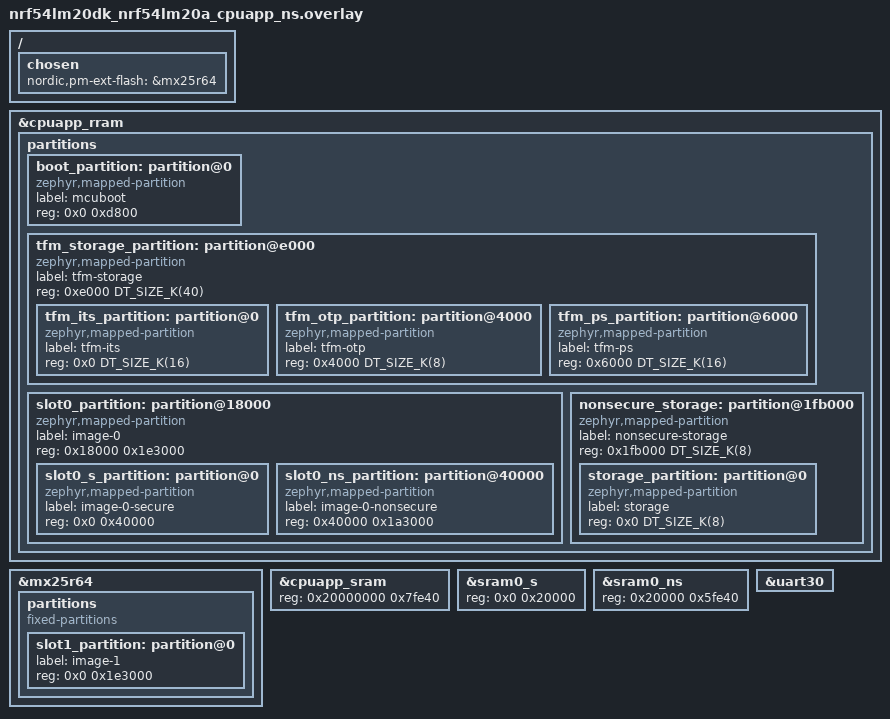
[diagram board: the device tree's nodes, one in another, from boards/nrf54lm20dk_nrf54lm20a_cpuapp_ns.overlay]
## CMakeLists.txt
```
#
# Copyright (c) 2020 Nordic Semiconductor
#
# SPDX-License-Identifier: LicenseRef-Nordic-5-Clause
#

cmake_minimum_required(VERSION 3.20.0)

find_package(Zephyr REQUIRED HINTS $ENV{ZEPHYR_BASE})

project(azure_iot_hub)

# NORDIC SDK APP START
target_sources(app PRIVATE src/main.c)
# NORDIC SDK APP END

zephyr_include_directories(src)
```

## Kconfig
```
#
# Copyright (c) 2022 Nordic Semiconductor ASA
#
# SPDX-License-Identifier: LicenseRef-Nordic-5-Clause
#

menu "Azure IoT Hub sample"

module = AZURE_IOT_HUB_SAMPLE
module-str = Azure IoT Hub sample
source "$(ZEPHYR_BASE)/subsys/logging/Kconfig.template.log_config"

config AZURE_IOT_HUB_SAMPLE_DEVICE_ID_USE_HW_ID
	bool "Use HW ID as device ID"
	select HW_ID_LIBRARY
	help
	  Use the devices's hardware ID as device ID when connecting to Azure IOT Hub

config AZURE_IOT_HUB_SAMPLE_CONNECTION_RETRY_TIMEOUT_SECONDS
	int "Number of seconds between each Azure IoT Hub connection retry"
	default 30
	help
	  If the connection fails, the sample tries to connect again at this interval.

endmenu

menu "Zephyr Kernel"
source "Kconfig.zephyr"
endmenu
```

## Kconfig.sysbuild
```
#
# Copyright (c) 2024 Nordic Semiconductor
#
# SPDX-License-Identifier: LicenseRef-Nordic-5-Clause
#

choice BOOTLOADER
	default BOOTLOADER_MCUBOOT if !BOARD_NATIVE_SIM
endchoice

config WIFI_NRF70
	default y if BOARD_NRF7002DK_NRF5340_CPUAPP_NS || \
		BOARD_NRF54LM20DK_NRF54LM20A_CPUAPP_NS || \
		BOARD_NRF54LM20DK_NRF54LM20B_CPUAPP_NS

source "share/sysbuild/Kconfig"
```

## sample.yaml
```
sample:
  name: Azure IoT Hub sample
tests:
  sample.net.azure_iot_hub:
    sysbuild: true
    build_only: true
    integration_platforms:
      - nrf9151dk/nrf9151/ns
      - native_sim
    platform_allow:
      - nrf9151dk/nrf9151/ns
      - native_sim
    tags:
      - ci_build
      - sysbuild
      - ci_samples_net
  sample.net.azure_iot_hub.wifi:
    sysbuild: true
    build_only: true
    integration_platforms:
      - nrf7002dk/nrf5340/cpuapp/ns
    platform_allow:
      - nrf7002dk/nrf5340/cpuapp/ns
    extra_args:
      - azure_iot_hub_EXTRA_CONF_FILE="wifi.conf"
    tags:
      - ci_build
      - sysbuild
      - ci_samples_net
  sample.net.azure_iot_hub.nrf7120.wifi:
    sysbuild: true
    build_only: true
    integration_platforms:
      - nrf7120dk/nrf7120/cpuapp/ns
    platform_allow:
      - nrf7120dk/nrf7120/cpuapp/ns
    extra_args:
      - azure_iot_hub_EXTRA_CONF_FILE="wifi.conf"
    tags:
      - ci_build
      - sysbuild
      - ci_samples_net
  sample.net.azure_iot_hub.nrf54lm20_nrf7002eb2.wifi:
    sysbuild: true
    build_only: true
    build_on_all: true
    integration_platforms:
      - nrf54lm20dk/nrf54lm20a/cpuapp/ns
      - nrf54lm20dk/nrf54lm20b/cpuapp/ns
    platform_allow:
      - nrf54lm20dk/nrf54lm20a/cpuapp/ns
      - nrf54lm20dk/nrf54lm20b/cpuapp/ns
    extra_args:
      - azure_iot_hub_SHIELD="nrf7002eb2"
      - azure_iot_hub_EXTRA_CONF_FILE="wifi.conf"
    tags:
      - ci_build
      - sysbuild
      - ci_samples_net
  sample.net.azure_iot_hub.dps:
    sysbuild: true
    build_only: true
    integration_platforms:
      - nrf9151dk/nrf9151/ns
    platform_allow:
      - nrf9151dk/nrf9151/ns
    extra_args:
      - azure_iot_hub_EXTRA_CONF_FILE=dps.conf
    extra_configs:
      - CONFIG_AZURE_IOT_HUB_DPS_ID_SCOPE="test-scope"
    tags:
      - ci_build
      - sysbuild
      - ci_samples_net
  sample.net.azure_iot_hub.dps.wifi:
    sysbuild: true
    build_only: true
    integration_platforms:
      - nrf7002dk/nrf5340/cpuapp/ns
    platform_allow:
      - nrf7002dk/nrf5340/cpuapp/ns
    extra_args:
      - azure_iot_hub_EXTRA_CONF_FILE="wifi.conf;dps.conf"
    extra_configs:
      - CONFIG_AZURE_IOT_HUB_DPS_ID_SCOPE="test-scope"
    tags:
      - ci_build
      - sysbuild
      - ci_samples_net
  sample.net.azure_iot_hub.dps.nrf7120.wifi:
    sysbuild: true
    build_only: true
    integration_platforms:
      - nrf7120dk/nrf7120/cpuapp/ns
    platform_allow:
      - nrf7120dk/nrf7120/cpuapp/ns
    extra_args:
      - azure_iot_hub_EXTRA_CONF_FILE="wifi.conf;dps.conf"
    extra_configs:
      - CONFIG_AZURE_IOT_HUB_DPS_ID_SCOPE="test-scope"
    tags:
      - ci_build
      - sysbuild
      - ci_samples_net
  sample.net.azure_iot_hub.dps.nrf54lm20_nrf7002eb2.wifi:
    sysbuild: true
    build_only: true
    build_on_all: true
    integration_platforms:
      - nrf54lm20dk/nrf54lm20a/cpuapp/ns
      - nrf54lm20dk/nrf54lm20b/cpuapp/ns
    platform_allow:
      - nrf54lm20dk/nrf54lm20a/cpuapp/ns
      - nrf54lm20dk/nrf54lm20b/cpuapp/ns
    extra_args:
      - azure_iot_hub_SHIELD="nrf7002eb2"
      - azure_iot_hub_EXTRA_CONF_FILE="wifi.conf;dps.conf"
    extra_configs:
      - CONFIG_AZURE_IOT_HUB_DPS_ID_SCOPE="test-scope"
    tags:
      - ci_build
      - sysbuild
      - ci_samples_net
```

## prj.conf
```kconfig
#
# Copyright (c) 2020 Nordic Semiconductor ASA
#
# SPDX-License-Identifier: LicenseRef-Nordic-5-Clause
#

# General config
CONFIG_REBOOT=y
CONFIG_ASSERT=y

# Logging
CONFIG_LOG=y
CONFIG_LOG_MODE_DEFERRED=y

# Network
CONFIG_NETWORKING=y
CONFIG_NET_NATIVE=y
CONFIG_NET_IPV4=y
CONFIG_NET_CONNECTION_MANAGER=y

# Azure IoT Hub library
CONFIG_AZURE_IOT_HUB=y
CONFIG_AZURE_IOT_HUB_DEVICE_ID="my-device"
# Host name must be configured if DPS is not used
CONFIG_AZURE_IOT_HUB_HOSTNAME=""
# Change the security tag to the tag where Azure IoT Hub certificates
# are provisioned
CONFIG_MQTT_HELPER_SEC_TAG=10
CONFIG_MQTT_HELPER_STACK_SIZE=8192

# Uncomment to get more verbose logging when debugging
# CONFIG_AZURE_IOT_HUB_LOG_LEVEL_DBG=y

# MQTT - Maximum MQTT keepalive timeout specified by Azure IoT Hub
CONFIG_MQTT_KEEPALIVE=1767

# cJSON
CONFIG_CJSON_LIB=y

# Settings, needed for Azure Device Provisioning Service
CONFIG_FLASH=y
CONFIG_FLASH_MAP=y
CONFIG_FCB=y
CONFIG_SETTINGS=y
CONFIG_SETTINGS_FCB=n
CONFIG_MPU_ALLOW_FLASH_WRITE=y
```

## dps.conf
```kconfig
#
# Copyright (c) 2022 Nordic Semiconductor ASA
#
# SPDX-License-Identifier: LicenseRef-Nordic-5-Clause
#

CONFIG_AZURE_IOT_HUB_DPS=y

# The ID scope can be omitted and provided at run time
CONFIG_AZURE_IOT_HUB_DPS_ID_SCOPE=""

CONFIG_NVS=y
CONFIG_SETTINGS_NVS=y
```

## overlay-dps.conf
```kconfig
#
# Copyright (c) 2022 Nordic Semiconductor ASA
#
# SPDX-License-Identifier: LicenseRef-Nordic-5-Clause
#

CONFIG_AZURE_IOT_HUB_DPS=y

# The ID scope can be omitted and provided at run time
CONFIG_AZURE_IOT_HUB_DPS_ID_SCOPE=""
```

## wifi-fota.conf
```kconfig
#
# Copyright (c) 2026 Nordic Semiconductor ASA
#
# SPDX-License-Identifier: LicenseRef-Nordic-5-Clause
#

# Azure FOTA over MCUboot.

# Azure FOTA
CONFIG_AZURE_FOTA=y
CONFIG_AZURE_FOTA_APP_VERSION_AUTO=n
CONFIG_AZURE_FOTA_TLS=y
# Change the security tag to the tag where the certificates are provisioned
# for the server where the FOTA image is hosted
CONFIG_AZURE_FOTA_SEC_TAG=11
CONFIG_FOTA_DOWNLOAD=y
CONFIG_DFU_TARGET=y

# FOTA storage backend: MCUboot image manager + streaming downloader
CONFIG_FLASH=y
CONFIG_FLASH_MAP=y
CONFIG_MCUBOOT_IMG_MANAGER=y
CONFIG_IMG_MANAGER=y
CONFIG_STREAM_FLASH=y
CONFIG_IMG_ERASE_PROGRESSIVELY=y
CONFIG_DOWNLOADER=y
CONFIG_DOWNLOADER_STACK_SIZE=4096
```

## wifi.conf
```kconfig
#
# Copyright (c) 2026 Nordic Semiconductor ASA
#
# SPDX-License-Identifier: LicenseRef-Nordic-5-Clause
#

# Common Wi-Fi + networking + TLS configuration shared by all Wi-Fi builds of
# this sample (nRF70 and nRF71).

# Logging
CONFIG_NET_LOG=y

# Wi-Fi
CONFIG_WIFI=y
CONFIG_WIFI_NM_WPA_SUPPLICANT=y
CONFIG_WIFI_NM_WPA_SUPPLICANT_LOG_LEVEL_ERR=y
CONFIG_WIFI_NRF70_LOG_LEVEL_ERR=y
CONFIG_NET_L2_ETHERNET=y

# nRF70/nRF71 driver tuning. The two drivers use different symbol prefixes (NRF70_* for the
# external nRF7002, NRF71_* for the integrated nRF7120 Wi-Fi), so both sets are listed with
# matching values. Each set is a no-op on the board that uses the other driver.
CONFIG_WIFI_CREDENTIALS=y

# Zephyr NET Connection Manager Connectivity layer.
CONFIG_L2_WIFI_CONNECTIVITY=y
CONFIG_L2_WIFI_CONNECTIVITY_AUTO_CONNECT=n
CONFIG_L2_WIFI_CONNECTIVITY_AUTO_DOWN=n

# DNS
CONFIG_DNS_RESOLVER=y
CONFIG_NET_SOCKETS_DNS_TIMEOUT=30000

# NET sockets
CONFIG_NET_SOCKETS=y
CONFIG_NET_TCP=y
CONFIG_NET_UDP=y
CONFIG_NET_SOCKETS_OFFLOAD=n
CONFIG_NET_DHCPV4=y
# Run DHCPv6 on RA, covering both stateful and stateless configurations
CONFIG_NET_DHCPV6=y
CONFIG_NET_DHCPV6_START_ON_RA=y
CONFIG_NET_CONTEXT_SNDTIMEO=y
CONFIG_NET_CONTEXT_RCVTIMEO=y

# Shell
CONFIG_SHELL=y
CONFIG_SHELL_STACK_SIZE=8192
CONFIG_NET_L2_WIFI_SHELL=y

# General
CONFIG_POSIX_TIMERS=y
CONFIG_HW_ID_LIBRARY=y
CONFIG_HW_ID_LIBRARY_SOURCE_NET_MAC=y
CONFIG_DK_LIBRARY=y

# Heap and stacks
CONFIG_MAIN_STACK_SIZE=6144
CONFIG_SYSTEM_WORKQUEUE_STACK_SIZE=4096
CONFIG_HEAP_MEM_POOL_SIZE=40144
CONFIG_HEAP_MEM_POOL_IGNORE_MIN=y
CONFIG_NET_RX_STACK_SIZE=4096
CONFIG_NET_SOCKETS_SERVICE_STACK_SIZE=2048
CONFIG_NRF_WIFI_DATA_HEAP_SIZE=65536

# TLS networking
CONFIG_NET_SOCKETS_SOCKOPT_TLS=y
CONFIG_NET_SOCKETS_ENABLE_DTLS=n
CONFIG_NET_SOCKETS_TLS_MAX_CONTEXTS=2
# Persist TLS credentials across reboots.
CONFIG_TLS_CREDENTIALS_BACKEND_PROTECTED_STORAGE=y

# mbedTLS
CONFIG_MBEDTLS=y
CONFIG_MBEDTLS_ENABLE_HEAP=y
# Fits the MQTT and FOTA download TLS connections at the same time.
CONFIG_MBEDTLS_HEAP_SIZE=98304
CONFIG_MBEDTLS_SSL_KEEP_PEER_CERTIFICATE=n
CONFIG_MBEDTLS_SSL_SERVER_NAME_INDICATION=y
# Set MPI (Multiple Precision Integer) size limit to 512 bytes for handling of 4 kb certificates
# in cryptographic operations.
CONFIG_MBEDTLS_MPI_MAX_SIZE=512
# PSA crypto not covered by the ciphersuite: ECDSA for server cert chain verification
CONFIG_PSA_WANT_ALG_ECDSA=y
# Azure Blob Storage, the FOTA host, uses an RSA 4096-bit CA certificate chain.
# Keep RSA 2048 enabled for the Azure IoT Hub chain, as it is no longer the
# default when another key size is enabled.
CONFIG_PSA_WANT_RSA_KEY_SIZE_2048=y
CONFIG_PSA_WANT_RSA_KEY_SIZE_4096=y
# TLS crypto via one ciphersuite config
CONFIG_MBEDTLS_CIPHERSUITE_TLS_ECDHE_RSA_WITH_AES_128_GCM_SHA256=y

# Enable LTO to save flash memory
CONFIG_LTO=y
CONFIG_ISR_TABLES_LOCAL_DECLARATION=y

# Floating-point printf support
CONFIG_CBPRINTF_FP_SUPPORT=y
CONFIG_LOG_PROCESS_THREAD_STACK_SIZE=4096

# Azure FOTA
CONFIG_AZURE_FOTA=y
CONFIG_AZURE_FOTA_APP_VERSION_AUTO=n
CONFIG_AZURE_FOTA_TLS=y
# Set the same security tag as for CONFIG_MQTT_HELPER_SEC_TAG since the same CA
# certificate is used to validate the server hosting the firmware image.
CONFIG_AZURE_FOTA_SEC_TAG=10
CONFIG_FOTA_DOWNLOAD=y
CONFIG_DFU_TARGET=y

# FOTA storage backend: MCUboot image manager + streaming downloader
CONFIG_FLASH=y
CONFIG_FLASH_MAP=y
CONFIG_MCUBOOT_IMG_MANAGER=y
CONFIG_IMG_MANAGER=y
CONFIG_STREAM_FLASH=y
CONFIG_IMG_ERASE_PROGRESSIVELY=y
CONFIG_DOWNLOADER=y
CONFIG_DOWNLOADER_STACK_SIZE=4096
```

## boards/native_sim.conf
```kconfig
#
# Copyright (c) 2023 Nordic Semiconductor ASA
#
# SPDX-License-Identifier: LicenseRef-Nordic-5-Clause
#

# Heap and stacks
CONFIG_HEAP_MEM_POOL_SIZE=1280

# Networking config
CONFIG_NET_TCP=y
CONFIG_NET_UDP=y
CONFIG_NET_SOCKETS=y
CONFIG_POSIX_API=y
CONFIG_NET_SOCKETS_SOCKOPT_TLS=y
CONFIG_NET_PKT_RX_COUNT=32
CONFIG_NET_PKT_TX_COUNT=32
CONFIG_NET_BUF_RX_COUNT=32
CONFIG_NET_BUF_TX_COUNT=32
CONFIG_NET_IF_UNICAST_IPV6_ADDR_COUNT=3
CONFIG_NET_IF_MCAST_IPV6_ADDR_COUNT=4
CONFIG_NET_MAX_CONTEXTS=10
CONFIG_NET_L2_ETHERNET=y
CONFIG_NET_CONTEXT_SNDTIMEO=y

CONFIG_ETH_NATIVE_TAP=y

# Network driver config
CONFIG_TEST_RANDOM_GENERATOR=y

# TLS configuration
CONFIG_MBEDTLS=y
CONFIG_MBEDTLS_ENABLE_HEAP=y
CONFIG_MBEDTLS_HEAP_SIZE=40000
CONFIG_MBEDTLS_SSL_MAX_CONTENT_LEN=7168
CONFIG_MBEDTLS_PEM_PARSE_C=y
CONFIG_MBEDTLS_PEM_WRITE_C=y
CONFIG_MBEDTLS_CIPHERSUITE_TLS_ECDHE_RSA_WITH_AES_128_CBC_SHA256=y

# DNS
CONFIG_DNS_RESOLVER=y
CONFIG_DNS_SERVER_IP_ADDRESSES=y
CONFIG_DNS_SERVER1="8.8.8.8"
CONFIG_DNS_RESOLVER_MAX_SERVERS=2

# Network address config
CONFIG_NET_CONFIG_SETTINGS=y
CONFIG_NET_CONFIG_NEED_IPV4=y
CONFIG_NET_CONFIG_MY_IPV4_ADDR="192.0.2.1"
CONFIG_NET_CONFIG_MY_IPV4_GW="192.0.2.2"

# Azure IoT Hub library
CONFIG_MQTT_HELPER_SEC_TAG=201
```

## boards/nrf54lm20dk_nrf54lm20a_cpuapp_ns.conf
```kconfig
#
# Copyright (c) 2026 Nordic Semiconductor ASA
#
# SPDX-License-Identifier: LicenseRef-Nordic-5-Clause
#

# External flash driver for the MCUboot secondary slot
CONFIG_SPI=y
CONFIG_SPI_NOR=y
CONFIG_SPI_NOR_SFDP_DEVICETREE=y

# Necessary for TLS with MM-less IOVEC.
# 36864 = 2 * MBEDTLS_SSL_MAX_CONTENT_LEN (16384) + overhead
CONFIG_TFM_CRYPTO_IOVEC_BUFFER_SIZE=36864

# Configure TF-M
CONFIG_TFM_PROFILE_TYPE_NOT_SET=y
# TF-M and nRF7002EB2 shield use the same UART30. TF-M assigns UART30 to secure environment, which
# causes BusFault when app tries to access it. Disabling logging in TF-M prevent it using UART30.
CONFIG_TFM_LOG_LEVEL_SILENCE=y
```

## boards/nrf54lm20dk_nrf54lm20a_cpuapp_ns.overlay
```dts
/*
 * Copyright (c) 2026 Nordic Semiconductor ASA
 *
 * SPDX-License-Identifier: LicenseRef-Nordic-5-Clause
 */

/ {
	/* Configure partition manager to use mx25r64 as the external flash */
	chosen {
		nordic,pm-ext-flash = &mx25r64;
	};
};

/delete-node/ &slot0_partition;
/delete-node/ &tfm_ps_partition;
/delete-node/ &tfm_its_partition;
/delete-node/ &tfm_otp_partition;
/delete-node/ &slot0_ns_partition;
/delete-node/ &storage_partition;

&cpuapp_rram {
	partitions {
		boot_partition: partition@0 {
			compatible = "zephyr,mapped-partition";
			label = "mcuboot";
			reg = <0x0 0xd800>;
		};

		tfm_storage_partition: partition@e000 {
			compatible = "zephyr,mapped-partition";
			label = "tfm-storage";
			reg = <0xe000 DT_SIZE_K(40)>;
			ranges = <0x0 0xe000 DT_SIZE_K(40)>;
			#address-cells = <1>;
			#size-cells = <1>;

			tfm_its_partition: partition@0 {
				compatible = "zephyr,mapped-partition";
				label = "tfm-its";
				reg = <0x0 DT_SIZE_K(16)>;
			};

			tfm_otp_partition: partition@4000 {
				compatible = "zephyr,mapped-partition";
				label = "tfm-otp";
				reg = <0x4000 DT_SIZE_K(8)>;
			};

			tfm_ps_partition: partition@6000 {
				compatible = "zephyr,mapped-partition";
				label = "tfm-ps";
				reg = <0x6000 DT_SIZE_K(16)>;
			};
		};

		slot0_partition: partition@18000 {
			compatible = "zephyr,mapped-partition";
			label = "image-0";
			reg = <0x18000 0x1e3000>;
			ranges = <0x0 0x18000 0x1e3000>;
			#address-cells = <1>;
			#size-cells = <1>;

			slot0_s_partition: partition@0 {
				compatible = "zephyr,mapped-partition";
				label = "image-0-secure";
				reg = <0x0 0x40000>;
			};

			slot0_ns_partition: partition@40000 {
				compatible = "zephyr,mapped-partition";
				label = "image-0-nonsecure";
				reg = <0x40000 0x1a3000>;
			};
		};

		nonsecure_storage: partition@1fb000 {
			compatible = "zephyr,mapped-partition";
			label = "nonsecure-storage";
			reg = <0x1fb000 DT_SIZE_K(8)>;
			ranges = <0x0 0x1fb000 DT_SIZE_K(8)>;
			#address-cells = <1>;
			#size-cells = <1>;

			storage_partition: partition@0 {
				compatible = "zephyr,mapped-partition";
				label = "storage";
				reg = <0x0 DT_SIZE_K(8)>;
			};
		};
	};
};

&mx25r64 {
	status = "okay";

	partitions {
		compatible = "fixed-partitions";
		#address-cells = <1>;
		#size-cells = <1>;

		slot1_partition: partition@0 {
			label = "image-1";
			reg = <0x0 0x1e3000>;
		};
	};
};

/*
 * CPUAPP SRAM TrustZone split: TF-M uses the first 128 KiB (&sram0_s, reg 0x20000); the NS
 * workload uses the remainder (&sram0_ns). These sizes must match the TF-M platform RAM
 * layout for nRF54LM20.
 */
&cpuapp_sram {
	reg = <0x20000000 0x7fe40>;
	ranges = <0x0 0x20000000 0x7fe40>;
};

&sram0_s {
	reg = <0x0 0x20000>;
	ranges = <0x0 0x0 0x20000>;
};

&sram0_ns {
	reg = <0x20000 0x5fe40>;
	ranges = <0x0 0x20000 0x5fe40>;
};

/*
 * Board NS DTS keeps &uart30 disabled for the default TF-M UARTE30 logging case.
 * With CONFIG_TFM_LOG_LEVEL_SILENCE=y TF-M does not use that UART; re-enable UARTE30 for NS.
 */
&uart30 {
	status = "okay";
};

/*
 * This layout redefines the flash partition map, dropping partitions that the
 * upstream nordic-tz-secure/-nonsecure descriptors reference. Remove the
 * descriptors so they do not hold dangling phandles (restores the behaviour
 * from before the descriptors were introduced).
 */
/ {
	/delete-node/ nordic-tz-secure;
	/delete-node/ nordic-tz-nonsecure;
};
```

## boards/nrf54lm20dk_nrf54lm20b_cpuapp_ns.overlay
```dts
/*
 * Copyright (c) 2026 Nordic Semiconductor ASA
 *
 * SPDX-License-Identifier: LicenseRef-Nordic-5-Clause
 */

/delete-node/ &slot0_s_partition;
/delete-node/ &tfm_ps_partition;
/delete-node/ &tfm_its_partition;
/delete-node/ &tfm_otp_partition;
/delete-node/ &slot0_ns_partition;
/delete-node/ &storage_partition;

&cpuapp_rram {
	partitions {
		boot_partition: partition@0 {
			compatible = "zephyr,mapped-partition";
			label = "mcuboot";
			reg = <0x0 0x10000>;
		};

		tfm_storage_partition: partition@10000 {
			compatible = "zephyr,mapped-partition";
			label = "tfm-storage";
			reg = <0x10000 DT_SIZE_K(40)>;
			ranges = <0x0 0x10000 DT_SIZE_K(40)>;
			#address-cells = <1>;
			#size-cells = <1>;

			tfm_its_partition: partition@0 {
				compatible = "zephyr,mapped-partition";
				label = "tfm-its";
				reg = <0x0 DT_SIZE_K(16)>;
			};

			tfm_otp_partition: partition@4000 {
				compatible = "zephyr,mapped-partition";
				label = "tfm-otp";
				reg = <0x4000 DT_SIZE_K(8)>;
			};

			tfm_ps_partition: partition@6000 {
				compatible = "zephyr,mapped-partition";
				label = "tfm-ps";
				reg = <0x6000 DT_SIZE_K(16)>;
			};
		};

		slot0_partition: partition@1a000 {
			compatible = "zephyr,mapped-partition";
			label = "image-0";
			reg = <0x1a000 0x1e1000>;
			ranges = <0x0 0x1a000 0x1e1000>;
			#address-cells = <1>;
			#size-cells = <1>;

			slot0_s_partition: partition@0 {
				compatible = "zephyr,mapped-partition";
				label = "image-0-secure";
				reg = <0x0 0x40000>;
			};

			slot0_ns_partition: partition@40000 {
				compatible = "zephyr,mapped-partition";
				label = "image-0-nonsecure";
				reg = <0x40000 0x1a1000>;
			};
		};

		nonsecure_storage: partition@1fb000 {
			compatible = "zephyr,mapped-partition";
			label = "nonsecure-storage";
			reg = <0x1fb000 DT_SIZE_K(8)>;
			ranges = <0x0 0x1fb000 DT_SIZE_K(8)>;
			#address-cells = <1>;
			#size-cells = <1>;

			storage_partition: partition@0 {
				compatible = "zephyr,mapped-partition";
				label = "storage";
				reg = <0x0 DT_SIZE_K(8)>;
			};
		};
	};
};

&mx25r64 {
	status = "okay";

	partitions {
		compatible = "fixed-partitions";
		#address-cells = <1>;
		#size-cells = <1>;

		slot1_partition: partition@0 {
			label = "image-1";
			reg = <0x0 0x1e1000>;
		};
	};
};

/*
 * CPUAPP SRAM TrustZone split: TF-M uses the first 128 KiB (&sram0_s, reg 0x20000); the NS
 * workload uses the remainder (&sram0_ns). These sizes must match the TF-M platform RAM
 * layout for nRF54LM20.
 */
&cpuapp_sram {
	reg = <0x20000000 0x7fe40>;
	ranges = <0x0 0x20000000 0x7fe40>;
};

&sram0_s {
	reg = <0x0 0x20000>;
	ranges = <0x0 0x0 0x20000>;
};

&sram0_ns {
	reg = <0x20000 0x5fe40>;
	ranges = <0x0 0x20000 0x5fe40>;
};

/*
 * Board NS DTS keeps &uart30 disabled for the default TF-M UARTE30 logging case.
 * With CONFIG_TFM_LOG_LEVEL_SILENCE=y TF-M does not use that UART; re-enable UARTE30 for NS.
 */
&uart30 {
	status = "okay";
};
```

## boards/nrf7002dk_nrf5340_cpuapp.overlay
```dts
/*
 * Copyright (c) 2023 Nordic Semiconductor ASA
 *
 * SPDX-License-Identifier: LicenseRef-Nordic-5-Clause
 */

 / {
	/* Configure partition manager to use mx25r64 as the external flash */
	chosen {
		nordic,pm-ext-flash = &mx25r64;
	};
};

&mx25r64 {
	status = "okay";
};
```

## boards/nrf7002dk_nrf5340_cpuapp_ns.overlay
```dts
/*
 * Copyright (c) 2023 Nordic Semiconductor ASA
 *
 * SPDX-License-Identifier: LicenseRef-Nordic-5-Clause
 */

/delete-node/ &boot_partition;
/delete-node/ &slot0_partition;
/delete-node/ &slot1_partition;
/delete-node/ &tfm_its_partition;
/delete-node/ &tfm_otp_partition;
/delete-node/ &tfm_ps_partition;
/delete-node/ &storage_partition;

&flash0 {
	partitions {
		boot_partition: partition@0 {
			compatible = "zephyr,mapped-partition";
			label = "mcuboot";
			reg = <0x0 0x10000>;
		};

		/* Larger NS slot than 0xc0000 for MCUboot signed image; */
		/* 8 KiB below aws_iot for settings. */
		slot0_partition: partition@10000 {
			compatible = "zephyr,mapped-partition";
			label = "image-0";
			reg = <0x10000 0xe2000>;
			ranges = <0x0 0x10000 0xe2000>;
			#address-cells = <1>;
			#size-cells = <1>;

			slot0_s_partition: partition@0 {
				compatible = "zephyr,mapped-partition";
				label = "image-0-secure";
				reg = <0x0 0x20000>;
			};

			slot0_ns_partition: partition@20000 {
				compatible = "zephyr,mapped-partition";
				label = "image-0-nonsecure";
				reg = <0x20000 0xc2000>;
			};
		};

		nonsecure_storage: partition@f2000 {
			compatible = "zephyr,mapped-partition";
			label = "nonsecure-storage";
			reg = <0xf2000 DT_SIZE_K(8)>;
			ranges = <0x0 0xf2000 DT_SIZE_K(8)>;
			#address-cells = <1>;
			#size-cells = <1>;

			storage_partition: partition@0 {
				compatible = "zephyr,mapped-partition";
				label = "storage";
				reg = <0x0 DT_SIZE_K(8)>;
			};
		};

		tfm_storage_partition: partition@f4000 {
			compatible = "zephyr,mapped-partition";
			label = "tfm-storage";
			reg = <0xf4000 DT_SIZE_K(48)>;
			ranges = <0x0 0xf4000 DT_SIZE_K(48)>;
			#address-cells = <1>;
			#size-cells = <1>;

			tfm_its_partition: partition@0 {
				compatible = "zephyr,mapped-partition";
				label = "tfm-its";
				reg = <0x0 DT_SIZE_K(8)>;
			};

			tfm_otp_partition: partition@4000 {
				compatible = "zephyr,mapped-partition";
				label = "tfm-otp";
				reg = <0x4000 DT_SIZE_K(8)>;
			};

			tfm_ps_partition: partition@8000 {
				compatible = "zephyr,mapped-partition";
				label = "tfm-ps";
				reg = <0x8000 DT_SIZE_K(16)>;
			};
		};
	};
};

&mx25r64 {
	status = "okay";

	partitions {
		compatible = "fixed-partitions";
		#address-cells = <1>;
		#size-cells = <1>;

		slot1_partition: partition@0 {
			label = "image-1";
			reg = <0x0 0xe2000>;
		};
	};
};

/*
 * TrustZone SRAM split from devicetree (region_defs.h for TF-M). The secure image uses
 * 48 KiB (0xc000) at the base of cpuapp SRAM (&sram0_s); NS RAM begins at 0x20000000 + 0xc000.
 * &sram0_ns spans 0x74000 bytes; &sram0_ns_app is 0x64000 because the top 0x10000 (64 KiB)
 * within that NS window is sram0_shared for application/network-core IPC
 * (nrf5340_shared_sram_partition.dtsi), i.e. 0x64000 + 0x10000 == 0x74000.
 */
&sram0_s {
	reg = <0x0 0xc000>;
};

&sram0_ns {
	reg = <0xc000 0x74000>;
	ranges = <0x0 0xc000 0x74000>;
};

&sram0_ns_app {
	reg = <0x0 0x64000>;
};

/ {
	/delete-node/ nordic-tz-secure;
	/delete-node/ nordic-tz-nonsecure;

	nordic-tz-secure {
		compatible = "nordic,tz-secure";
		code-partitions = <&slot0_s_partition>;
		data-partitions = <&tfm_ps_partition>,
				  <&tfm_its_partition>,
				  <&tfm_otp_partition>;
	};

	nordic-tz-nonsecure {
		compatible = "nordic,tz-nonsecure";
		code-partitions = <&slot0_ns_partition>;
		data-partitions = <&storage_partition>;
	};
};
```

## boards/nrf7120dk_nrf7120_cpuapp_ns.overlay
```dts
/*
 * Copyright (c) 2026 Nordic Semiconductor ASA
 *
 * SPDX-License-Identifier: LicenseRef-Nordic-5-Clause
 */

/* Adjust RAM Size for TF-M */
&sram0_s {
	reg = <0x20000000 DT_SIZE_K(104)>;	/* 104 KB — TF-M */
};

&sram0_ns {
	reg = <0x2001a000 DT_SIZE_K(408)>;	/* 408 KB — App */
};
```

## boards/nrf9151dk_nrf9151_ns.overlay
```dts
/*
 * Copyright (c) 2026 Nordic Semiconductor ASA
 *
 * SPDX-License-Identifier: LicenseRef-Nordic-5-Clause
 */

#include <samples/cellular/nrf91_bootloader_partitions.dtsi>

#include <samples/cellular/nrf91_sram_partitions.dtsi>
```

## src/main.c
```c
/*
 * Copyright (c) 2020-2023 Nordic Semiconductor ASA
 *
 * SPDX-License-Identifier: LicenseRef-Nordic-5-Clause
 */


#include <stdio.h>
#include <stdlib.h>
#include <zephyr/kernel.h>
#include <zephyr/sys/reboot.h>
#include <zephyr/net/conn_mgr_connectivity.h>
#include <zephyr/dfu/mcuboot.h>
#include <net/azure_iot_hub.h>
#include <net/azure_iot_hub_dps.h>
#include <zephyr/logging/log.h>
#include <zephyr/logging/log_ctrl.h>

#include <dk_buttons_and_leds.h>
#include <cJSON.h>
#include <cJSON_os.h>

#include <hw_id.h>

#ifndef CONFIG_AZURE_IOT_HUB_DPS_TIMEOUT_SEC
#define CONFIG_AZURE_IOT_HUB_DPS_TIMEOUT_SEC 0
#endif

LOG_MODULE_REGISTER(azure_iot_hub_sample, CONFIG_AZURE_IOT_HUB_SAMPLE_LOG_LEVEL);

/* Macros used to subscribe to specific Zephyr net management events. */
#define L4_EVENT_MASK (NET_EVENT_L4_CONNECTED | NET_EVENT_L4_DISCONNECTED)
#define CONN_LAYER_EVENT_MASK (NET_EVENT_CONN_IF_FATAL_ERROR)

/* Interval [s] between sending events to the IoT hub. The value can be changed
 * by setting a new desired value for property 'telemetryInterval' in the
 * device twin document.
 */
#define EVENT_INTERVAL		20
#define RECV_BUF_SIZE		1024
#define APP_WORK_Q_STACK_SIZE	KB(8)

static struct method_data {
	struct k_work work;
	char request_id[8];
	char name[32];
	char payload[200];
} method_data;
static struct k_work twin_report_work;
static struct k_work_delayable send_event_work;
static struct k_work_delayable reboot_work;

static char recv_buf[RECV_BUF_SIZE];
static void direct_method_handler(struct k_work *work);
static K_SEM_DEFINE(network_connected_sem, 0, 1);
static K_SEM_DEFINE(recv_buf_sem, 1, 1);
static atomic_t event_interval = EVENT_INTERVAL;

static bool dps_was_successful;

/* A work queue is created to execute potentially blocking calls from.
 * This is done to avoid blocking for example the system work queue for extended
 * periods of time.
 */
static K_THREAD_STACK_DEFINE(application_stack_area, APP_WORK_Q_STACK_SIZE);
static struct k_work_q application_work_q;

/* Returns a positive integer if the new interval can be parsed, otherwise -1 */
static int event_interval_get(char *buf)
{
	struct cJSON *root_obj, *desired_obj, *event_interval_obj;
	int new_interval = -1;

	root_obj = cJSON_Parse(buf);
	if (root_obj == NULL) {
		LOG_ERR("Could not parse properties object");
		return -1;
	}

	/* If the incoming buffer is a notification from the cloud about changes
	 * made to the device twin's "desired" properties, the root object will
	 * only contain the newly changed properties, and can be treated as if
	 * it is the "desired" object.
	 * If the incoming is the response to a request to receive the device
	 * twin, it will contain a "desired" object and a "reported" object,
	 * and we need to access that object instead of the root.
	 */
	desired_obj = cJSON_GetObjectItem(root_obj, "desired");
	if (desired_obj == NULL) {
		LOG_DBG("Incoming device twin document contains only the 'desired' object");

		desired_obj = root_obj;
	}

	/* Update only recognized properties. */
	event_interval_obj = cJSON_GetObjectItem(desired_obj,
						 "telemetryInterval");
	if (event_interval_obj == NULL) {
		LOG_DBG("No 'telemetryInterval' object found in the device twin document");

		goto clean_exit;
	}

	if (cJSON_IsString(event_interval_obj)) {
		new_interval = atoi(event_interval_obj->valuestring);
	} else if (cJSON_IsNumber(event_interval_obj)) {
		new_interval = event_interval_obj->valueint;
	} else {
		LOG_WRN("Invalid telemetry interval format received");
		goto clean_exit;
	}

clean_exit:
	cJSON_Delete(root_obj);
	k_sem_give(&recv_buf_sem);

	return new_interval;
}

static void event_interval_apply(int interval)
{
	if (interval <= 0) {
		return;
	}

	atomic_set(&event_interval, interval);
	k_work_reschedule_for_queue(&application_work_q, &send_event_work, K_NO_WAIT);
}

static void on_evt_twin_desired(char *buf, size_t len)
{
	if (k_sem_take(&recv_buf_sem, K_NO_WAIT) == 0) {
		if (len > sizeof(recv_buf) - 1) {
			LOG_ERR("Incoming data too big for buffer");
			return;
		}

		memcpy(recv_buf, buf, len);
		recv_buf[len] = '\0';
		k_work_submit_to_queue(&application_work_q, &twin_report_work);
	} else {
		LOG_WRN("Recv buffer is busy, data was not copied");
	}
}

static void on_evt_direct_method(struct azure_iot_hub_method *method)
{
	size_t request_id_len = MIN(sizeof(method_data.request_id) - 1, method->request_id.size);
	size_t name_len = MIN(sizeof(method_data.name) - 1, method->name.size);

	LOG_INF("Method name: %.*s", method->name.size, method->name.ptr);
	LOG_INF("Payload: %.*s", method->payload.size, method->payload.ptr);

	memcpy(method_data.request_id, method->request_id.ptr, request_id_len);

	method_data.request_id[request_id_len] = '\0';

	memcpy(method_data.name, method->name.ptr, name_len);
	method_data.name[name_len] = '\0';

	snprintk(method_data.payload, sizeof(method_data.payload),
		 "%.*s", method->payload.size, method->payload.ptr);

	k_work_submit_to_queue(&application_work_q, &method_data.work);
}

static void reboot_work_fn(struct k_work *work)
{
	ARG_UNUSED(work);

	log_flush();
	LOG_PANIC();
	sys_reboot(SYS_REBOOT_COLD);
}

static void azure_event_handler(struct azure_iot_hub_evt *const evt)
{
	switch (evt->type) {
	case AZURE_IOT_HUB_EVT_CONNECTING:
		LOG_INF("AZURE_IOT_HUB_EVT_CONNECTING");
		break;
	case AZURE_IOT_HUB_EVT_CONNECTED:
		LOG_INF("AZURE_IOT_HUB_EVT_CONNECTED");
		break;
	case AZURE_IOT_HUB_EVT_CONNECTION_FAILED:
		LOG_INF("AZURE_IOT_HUB_EVT_CONNECTION_FAILED");
		LOG_INF("Error code received from IoT Hub: %d",
			evt->data.err);
		break;
	case AZURE_IOT_HUB_EVT_DISCONNECTED:
		LOG_INF("AZURE_IOT_HUB_EVT_DISCONNECTED");
		break;
	case AZURE_IOT_HUB_EVT_READY:
		LOG_INF("AZURE_IOT_HUB_EVT_READY");

		/* All initializations and cloud connection were successful, now mark
		 * image as working so that we will not revert upon reboot.
		 */
		if (IS_ENABLED(CONFIG_BOOTLOADER_MCUBOOT)) {
			boot_write_img_confirmed();
		}

		/* The AZURE_IOT_HUB_EVT_READY event indicates that the
		 * IoT hub connection is established and interaction with the
		 * cloud can begin.
		 *
		 * The below work submission will cause send_event() to be
		 * call after 3 seconds.
		 */
		k_work_reschedule_for_queue(&application_work_q,
					    &send_event_work, K_NO_WAIT);
		break;
	case AZURE_IOT_HUB_EVT_DATA_RECEIVED:
		LOG_INF("AZURE_IOT_HUB_EVT_DATA_RECEIVED");
		LOG_INF("Received payload: %.*s",
			evt->data.msg.payload.size, evt->data.msg.payload.ptr);
		break;
	case AZURE_IOT_HUB_EVT_TWIN_RECEIVED:
		LOG_INF("AZURE_IOT_HUB_EVT_TWIN_RECEIVED");
		event_interval_apply(event_interval_get(evt->data.msg.payload.ptr));
		break;
	case AZURE_IOT_HUB_EVT_TWIN_DESIRED_RECEIVED:
		LOG_INF("AZURE_IOT_HUB_EVT_TWIN_DESIRED_RECEIVED");
		on_evt_twin_desired(evt->data.msg.payload.ptr, evt->data.msg.payload.size);
		break;
	case AZURE_IOT_HUB_EVT_DIRECT_METHOD:
		LOG_INF("AZURE_IOT_HUB_EVT_DIRECT_METHOD");
		on_evt_direct_method(&evt->data.method);
		break;
	case AZURE_IOT_HUB_EVT_TWIN_RESULT_SUCCESS:
		LOG_INF("AZURE_IOT_HUB_EVT_TWIN_RESULT_SUCCESS, ID: %.*s",
			evt->data.result.request_id.size, evt->data.result.request_id.ptr);
		break;
	case AZURE_IOT_HUB_EVT_TWIN_RESULT_FAIL:
		LOG_INF("AZURE_IOT_HUB_EVT_TWIN_RESULT_FAIL, ID %.*s, status %d",
			evt->data.result.request_id.size,
			evt->data.result.request_id.ptr,
			evt->data.result.status);
		break;
	case AZURE_IOT_HUB_EVT_PUBACK:
		LOG_INF("AZURE_IOT_HUB_EVT_PUBACK");
		break;
	case AZURE_IOT_HUB_EVT_FOTA_START:
		LOG_INF("AZURE_IOT_HUB_EVT_FOTA_START");
		break;
	case AZURE_IOT_HUB_EVT_FOTA_DONE:
		LOG_INF("AZURE_IOT_HUB_EVT_FOTA_DONE");
		LOG_INF("The device will reboot in 5 seconds to apply update");
		k_work_schedule(&reboot_work, K_SECONDS(5));
		break;
	case AZURE_IOT_HUB_EVT_FOTA_ERASE_PENDING:
		LOG_INF("AZURE_IOT_HUB_EVT_FOTA_ERASE_PENDING");
		break;
	case AZURE_IOT_HUB_EVT_FOTA_ERASE_DONE:
		LOG_INF("AZURE_IOT_HUB_EVT_FOTA_ERASE_DONE");
		break;
	case AZURE_IOT_HUB_EVT_FOTA_ERROR:
		LOG_ERR("AZURE_IOT_HUB_EVT_FOTA_ERROR: FOTA failed");
		break;
	case AZURE_IOT_HUB_EVT_ERROR:
		LOG_INF("AZURE_IOT_HUB_EVT_ERROR");
		break;
	default:
		LOG_ERR("Unknown Azure IoT Hub event type: %d", evt->type);
		break;
	}
}

static void send_event(struct k_work *work)
{
	int err;
	static char buf[60];
	ssize_t len;
	struct azure_iot_hub_msg msg = {
		.topic.type = AZURE_IOT_HUB_TOPIC_EVENT,
		.payload.ptr = buf,
		.qos = MQTT_QOS_0_AT_MOST_ONCE,
	};

	len = snprintk(buf, sizeof(buf),
		       "{\"temperature\":%d.%d,\"timestamp\":%d}",
		       25, k_uptime_get_32() % 10, k_uptime_get_32());
	if ((len < 0) || (len > sizeof(buf))) {
		LOG_ERR("Failed to populate event buffer");
		goto exit;
	}

	msg.payload.size = len;

	LOG_INF("Sending event:%s", buf);

	err = azure_iot_hub_send(&msg);
	if (err) {
		LOG_ERR("Failed to send event");
		goto exit;
	}

	LOG_INF("Event was successfully sent");
exit:
	if (atomic_get(&event_interval) <= 0) {
		LOG_ERR("The event reporting stops, interval is set to %ld",
		       atomic_get(&event_interval));
		return;
	}

	LOG_INF("Next event will be sent in %ld seconds", event_interval);
	k_work_reschedule_for_queue(&application_work_q, &send_event_work,
				    K_SECONDS(event_interval));
}

static void direct_method_handler(struct k_work *work)
{
	int err;
	static const char response[] = "{\"it\":\"worked\"}";

	/* Status code 200 indicates successful execution of direct method. */
	struct azure_iot_hub_result result = {
		.request_id = {
			.ptr = method_data.request_id,
			.size = strlen(method_data.request_id),
		},
		.status = 200,
		.payload.ptr = (char *)response,
		.payload.size = sizeof(response) - 1,
	};
	bool led_state = strncmp(method_data.payload, "0", 1) ? 1 : 0;

	if (strcmp(method_data.name, "led") != 0) {
		LOG_INF("Unknown direct method");
		return;
	}

	if (IS_ENABLED(CONFIG_DK_LIBRARY)) {
		err = dk_set_led(DK_LED1, led_state);
		if (err) {
			LOG_ERR("Failed to set LED, error: %d", err);
			return;
		}
	} else {
		LOG_INF("No hardware interface to set LED state to %d", led_state);
	}

	err = azure_iot_hub_method_respond(&result);
	if (err) {
		LOG_ERR("Failed to send direct method response");
	}
}

static void twin_report_work_fn(struct k_work *work)
{
	int err;
	char buf[100];
	ssize_t len;
	struct azure_iot_hub_msg data = {
		.topic.type = AZURE_IOT_HUB_TOPIC_TWIN_REPORTED,
		.payload.ptr = buf,
		.qos = MQTT_QOS_0_AT_MOST_ONCE,
	};
	int new_interval;

	new_interval = event_interval_get(recv_buf);
	if (new_interval < 0) {
		return;
	}

	len = snprintk(buf, sizeof(buf),
		       "{\"telemetryInterval\":%d}", new_interval);
	if (len <= 0) {
		LOG_ERR("Failed to create twin report");
		return;
	}

	data.payload.size = len;

	err = azure_iot_hub_send(&data);
	if (err) {
		LOG_ERR("Failed to send twin report");
		return;
	}

	/* Note that the new interval value is first applied here, because that
	 * will make the "reported" value in the device twin be in sync with
	 * the reality on the device. Other applications may decide
	 * to apply the desired properties regardless of whether the value is
	 * successfully reported or not.
	 */
	event_interval_apply(new_interval);
	LOG_INF("New telemetry interval has been applied: %d",  new_interval);
}

static void on_net_event_l4_connected(void)
{
	k_sem_give(&network_connected_sem);
}

static void on_net_event_l4_disconnected(void)
{
	(void)azure_iot_hub_disconnect();
}



static void l4_event_handler(uint64_t event, struct net_if *iface, void *info,
			     size_t info_length, void *user_data)
{
	switch (event) {
	case NET_EVENT_L4_CONNECTED:
		LOG_INF("Network connectivity established and IP address assigned");
		on_net_event_l4_connected();
		break;
	case NET_EVENT_L4_DISCONNECTED:
		LOG_INF("Network connectivity lost, no IP address assigned");
		on_net_event_l4_disconnected();
		break;
	default:
		return;
	}
}

static void connectivity_event_handler(uint64_t event, struct net_if *iface, void *info,
				       size_t info_length, void *user_data)
{
	if (event == NET_EVENT_CONN_IF_FATAL_ERROR) {
		LOG_ERR("Fatal error received from the connectivity layer, rebooting");
		log_flush();
		LOG_PANIC();
		sys_reboot(SYS_REBOOT_COLD);
		CODE_UNREACHABLE;
	}
}

/* Registered statically to not miss events raised before main() */
NET_MGMT_REGISTER_EVENT_HANDLER(l4_events, L4_EVENT_MASK, l4_event_handler, NULL);
NET_MGMT_REGISTER_EVENT_HANDLER(conn_events, CONN_LAYER_EVENT_MASK, connectivity_event_handler,
				NULL);

static void work_init(void)
{
	const struct k_work_queue_config cfg = {
		.name = "application_work_q",
	};

	k_work_init(&method_data.work, direct_method_handler);
	k_work_init(&twin_report_work, twin_report_work_fn);
	k_work_init_delayable(&send_event_work, send_event);
	k_work_init_delayable(&reboot_work, reboot_work_fn);

	k_work_queue_start(&application_work_q, application_stack_area,
		       K_THREAD_STACK_SIZEOF(application_stack_area),
		       K_HIGHEST_APPLICATION_THREAD_PRIO, &cfg);
}

static K_SEM_DEFINE(dps_done_sem, 0, 1);

static void dps_handler(enum azure_iot_hub_dps_reg_status status)
{
	switch (status) {
	case AZURE_IOT_HUB_DPS_REG_STATUS_NOT_STARTED:
		LOG_INF("DPS registration status: AZURE_IOT_HUB_DPS_REG_STATUS_NOT_STARTED");
		break;
	case AZURE_IOT_HUB_DPS_REG_STATUS_ASSIGNING:
		LOG_INF("DPS registration status: AZURE_IOT_HUB_DPS_REG_STATUS_ASSIGNING");
		break;
	case AZURE_IOT_HUB_DPS_REG_STATUS_ASSIGNED:
		LOG_INF("DPS registration status: AZURE_IOT_HUB_DPS_REG_STATUS_ASSIGNED");

		dps_was_successful = true;

		k_sem_give(&dps_done_sem);
		break;
	case AZURE_IOT_HUB_DPS_REG_STATUS_FAILED:
		LOG_INF("DPS registration status: AZURE_IOT_HUB_DPS_REG_STATUS_FAILED");

		dps_was_successful = false;

		k_sem_give(&dps_done_sem);
		break;
	default:
		LOG_WRN("Unhandled DPS status: %d", status);
		break;
	}
}

/* Run DPS using the provided device_id as registration ID. Upon success, the function will return
 * 0 and populate the hostname and device_id buffers with the assigned values.
 * The return value will be a negative integer in case of failure.
 */
static int dps_run(struct azure_iot_hub_buf *hostname, struct azure_iot_hub_buf *device_id)
{
	int err;
	struct azure_iot_hub_dps_config dps_cfg = {
		.handler = dps_handler,
		.reg_id = {
			.ptr = device_id->ptr,
			.size = strlen(device_id->ptr),
		},
		/* Default ID scope provided by Kconfig is used, so we will not change that. */
	};

	LOG_INF("Starting DPS");

	err = azure_iot_hub_dps_init(&dps_cfg);
	if (err) {
		LOG_ERR("azure_iot_hub_dps_init failed, error: %d", err);
		return err;
	}

	err = azure_iot_hub_dps_start();
	if (err == 0) {
		LOG_INF("The DPS process has started, timeout is set to %d seconds",
			CONFIG_AZURE_IOT_HUB_DPS_TIMEOUT_SEC);

		/* If DPS was started successfully, we wait for the semaphore that is given when the
		 * provisioning completes.
		 */

		(void)k_sem_take(&dps_done_sem, K_FOREVER);

		if (!dps_was_successful) {
			return -EFAULT;
		}

		/* The device was assigned, continue to retrieve the hostname. */
	} else if (err == -EALREADY) {
		LOG_INF("Already assigned to an IoT hub, skipping DPS");
	} else {
		LOG_ERR("DPS failed to start, error: %d", err);
		return err;
	}

	err = azure_iot_hub_dps_hostname_get(hostname);
	if (err) {
		LOG_ERR("Failed to get hostname, error: %d", err);
		return err;
	}

	err = azure_iot_hub_dps_device_id_get(device_id);
	if (err) {
		LOG_ERR("Failed to get device ID, error: %d", err);
		return err;
	}

	LOG_INF("Device ID \"%.*s\" assigned to IoT hub with hostname \"%.*s\"",
		device_id->size, device_id->ptr,
		hostname->size, hostname->ptr);

	return 0;
}

int main(void)
{
	int err;
	static char hostname[128] = CONFIG_AZURE_IOT_HUB_HOSTNAME;
	static char device_id[128] = CONFIG_AZURE_IOT_HUB_DEVICE_ID;
	static struct azure_iot_hub_config cfg = {
		.device_id = {
			.ptr = device_id,
		},
		.hostname = {
			.ptr = hostname,
		},
		.use_dps = true,
	};

	cfg.device_id.size = strlen(device_id);
	cfg.hostname.size = strlen(hostname);


	LOG_INF("Azure IoT Hub sample started");

	LOG_INF("Bringing network interface up and connecting to the network");

	/* Connecting to the configured connectivity layer.
	 * Wi-Fi or LTE depending on the board that the sample was built for.
	 */
	err = conn_mgr_all_if_up(true);
	if (err) {
		LOG_ERR("conn_mgr_if_connect, error: %d", err);
		return err;
	}

	err = conn_mgr_all_if_connect(true);
	if (err) {
		LOG_ERR("conn_mgr_all_if_connect, error: %d", err);
		return err;
	}

	if (IS_ENABLED(CONFIG_AZURE_IOT_HUB_SAMPLE_DEVICE_ID_USE_HW_ID)) {
		err = hw_id_get(device_id, ARRAY_SIZE(device_id));
		if (err) {
			LOG_ERR("Failed to retrieve device ID");
			return 0;
		}
		cfg.device_id.size = strlen(device_id);
	}

	LOG_INF("Device ID: %s", device_id);

	if (!IS_ENABLED(CONFIG_AZURE_IOT_HUB_DPS)) {
		LOG_INF("Host name: %s", hostname);
	}

	if (IS_ENABLED(CONFIG_DK_LIBRARY)) {
		dk_leds_init();
	}

	work_init();
	cJSON_Init();

	k_sem_take(&network_connected_sem, K_FOREVER);

	LOG_INF("Connected to network");

	if (IS_ENABLED(CONFIG_AZURE_IOT_HUB_DPS)) {
		/* Using the device ID as DPS registration ID. */
		err = dps_run(&cfg.hostname, &cfg.device_id);
		if (err) {
			LOG_ERR("Failed to run DPS, error: %d, terminating connection attempt",
				err);
			return 0;
		}
	}

	err = azure_iot_hub_init(azure_event_handler);
	if (err) {
		LOG_ERR("Azure IoT Hub could not be initialized, error: %d", err);
		return 0;
	}

	LOG_INF("Azure IoT Hub library initialized");

	err = azure_iot_hub_connect(&cfg);
	if (err < 0) {
		LOG_ERR("azure_iot_hub_connect failed: %d", err);
		return 0;
	}

	LOG_INF("Connection request sent to IoT Hub");

	/* After the connection to the IoT hub has been established, the
	 * Azure IoT Hub library will generate events when data is received.
	 * See azure_event_handler() for which actions will be taken on the
	 * various events.
	 */
	return 0;
}
```
